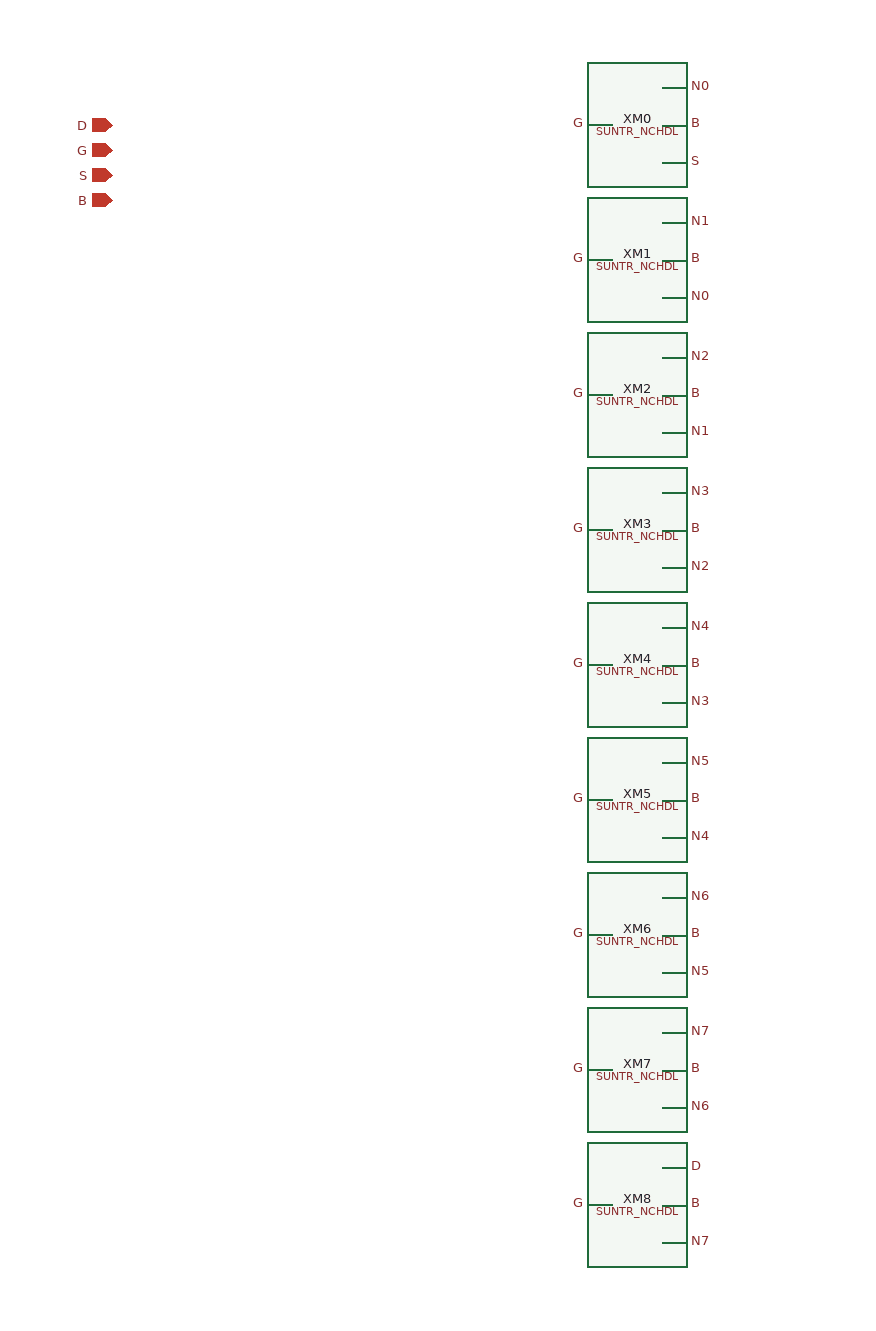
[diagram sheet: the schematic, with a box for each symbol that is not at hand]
v {xschem version=3.0.0 file_version=1.2 }
G {}
K {}
V {}
S {}
E {}
C {devices/iopin.sym} 0 0 0 0{name=p0 lab=D}
C {devices/iopin.sym} 0 20 0 0{name=p1 lab=G}
C {devices/iopin.sym} 0 40 0 0{name=p2 lab=S}
C {devices/iopin.sym} 0 60 0 0{name=p3 lab=B}
C {SUN_TR_SKY130NM/SUNTR_NCHDL.sym} 400 0 0 0 {name=XM0}
N 460.0 -30.0 440.0 -30.0{lab=N0}
C {devices/lab_pin.sym} 460.0 -30.0 2 0  {name=l0 sig_type=std_logic lab=N0 }
N 380.0 0.0 400.0 0.0{lab=G}
C {devices/lab_pin.sym} 380.0 0.0 0 0  {name=l1 sig_type=std_logic lab=G }
N 460.0 30.0 440.0 30.0{lab=S}
C {devices/lab_pin.sym} 460.0 30.0 2 0  {name=l2 sig_type=std_logic lab=S }
N 460.0 0.0 440.0 0.0{lab=B}
C {devices/lab_pin.sym} 460.0 0.0 2 0  {name=l3 sig_type=std_logic lab=B }
C {SUN_TR_SKY130NM/SUNTR_NCHDL.sym} 400 108.0 0 0 {name=XM1}
N 460.0 78.0 440.0 78.0{lab=N1}
C {devices/lab_pin.sym} 460.0 78.0 2 0  {name=l4 sig_type=std_logic lab=N1 }
N 380.0 108.0 400.0 108.0{lab=G}
C {devices/lab_pin.sym} 380.0 108.0 0 0  {name=l5 sig_type=std_logic lab=G }
N 460.0 138.0 440.0 138.0{lab=N0}
C {devices/lab_pin.sym} 460.0 138.0 2 0  {name=l6 sig_type=std_logic lab=N0 }
N 460.0 108.0 440.0 108.0{lab=B}
C {devices/lab_pin.sym} 460.0 108.0 2 0  {name=l7 sig_type=std_logic lab=B }
C {SUN_TR_SKY130NM/SUNTR_NCHDL.sym} 400 216.0 0 0 {name=XM2}
N 460.0 186.0 440.0 186.0{lab=N2}
C {devices/lab_pin.sym} 460.0 186.0 2 0  {name=l8 sig_type=std_logic lab=N2 }
N 380.0 216.0 400.0 216.0{lab=G}
C {devices/lab_pin.sym} 380.0 216.0 0 0  {name=l9 sig_type=std_logic lab=G }
N 460.0 246.0 440.0 246.0{lab=N1}
C {devices/lab_pin.sym} 460.0 246.0 2 0  {name=l10 sig_type=std_logic lab=N1 }
N 460.0 216.0 440.0 216.0{lab=B}
C {devices/lab_pin.sym} 460.0 216.0 2 0  {name=l11 sig_type=std_logic lab=B }
C {SUN_TR_SKY130NM/SUNTR_NCHDL.sym} 400 324.0 0 0 {name=XM3}
N 460.0 294.0 440.0 294.0{lab=N3}
C {devices/lab_pin.sym} 460.0 294.0 2 0  {name=l12 sig_type=std_logic lab=N3 }
N 380.0 324.0 400.0 324.0{lab=G}
C {devices/lab_pin.sym} 380.0 324.0 0 0  {name=l13 sig_type=std_logic lab=G }
N 460.0 354.0 440.0 354.0{lab=N2}
C {devices/lab_pin.sym} 460.0 354.0 2 0  {name=l14 sig_type=std_logic lab=N2 }
N 460.0 324.0 440.0 324.0{lab=B}
C {devices/lab_pin.sym} 460.0 324.0 2 0  {name=l15 sig_type=std_logic lab=B }
C {SUN_TR_SKY130NM/SUNTR_NCHDL.sym} 400 432.0 0 0 {name=XM4}
N 460.0 402.0 440.0 402.0{lab=N4}
C {devices/lab_pin.sym} 460.0 402.0 2 0  {name=l16 sig_type=std_logic lab=N4 }
N 380.0 432.0 400.0 432.0{lab=G}
C {devices/lab_pin.sym} 380.0 432.0 0 0  {name=l17 sig_type=std_logic lab=G }
N 460.0 462.0 440.0 462.0{lab=N3}
C {devices/lab_pin.sym} 460.0 462.0 2 0  {name=l18 sig_type=std_logic lab=N3 }
N 460.0 432.0 440.0 432.0{lab=B}
C {devices/lab_pin.sym} 460.0 432.0 2 0  {name=l19 sig_type=std_logic lab=B }
C {SUN_TR_SKY130NM/SUNTR_NCHDL.sym} 400 540.0 0 0 {name=XM5}
N 460.0 510.0 440.0 510.0{lab=N5}
C {devices/lab_pin.sym} 460.0 510.0 2 0  {name=l20 sig_type=std_logic lab=N5 }
N 380.0 540.0 400.0 540.0{lab=G}
C {devices/lab_pin.sym} 380.0 540.0 0 0  {name=l21 sig_type=std_logic lab=G }
N 460.0 570.0 440.0 570.0{lab=N4}
C {devices/lab_pin.sym} 460.0 570.0 2 0  {name=l22 sig_type=std_logic lab=N4 }
N 460.0 540.0 440.0 540.0{lab=B}
C {devices/lab_pin.sym} 460.0 540.0 2 0  {name=l23 sig_type=std_logic lab=B }
C {SUN_TR_SKY130NM/SUNTR_NCHDL.sym} 400 648.0 0 0 {name=XM6}
N 460.0 618.0 440.0 618.0{lab=N6}
C {devices/lab_pin.sym} 460.0 618.0 2 0  {name=l24 sig_type=std_logic lab=N6 }
N 380.0 648.0 400.0 648.0{lab=G}
C {devices/lab_pin.sym} 380.0 648.0 0 0  {name=l25 sig_type=std_logic lab=G }
N 460.0 678.0 440.0 678.0{lab=N5}
C {devices/lab_pin.sym} 460.0 678.0 2 0  {name=l26 sig_type=std_logic lab=N5 }
N 460.0 648.0 440.0 648.0{lab=B}
C {devices/lab_pin.sym} 460.0 648.0 2 0  {name=l27 sig_type=std_logic lab=B }
C {SUN_TR_SKY130NM/SUNTR_NCHDL.sym} 400 756.0 0 0 {name=XM7}
N 460.0 726.0 440.0 726.0{lab=N7}
C {devices/lab_pin.sym} 460.0 726.0 2 0  {name=l28 sig_type=std_logic lab=N7 }
N 380.0 756.0 400.0 756.0{lab=G}
C {devices/lab_pin.sym} 380.0 756.0 0 0  {name=l29 sig_type=std_logic lab=G }
N 460.0 786.0 440.0 786.0{lab=N6}
C {devices/lab_pin.sym} 460.0 786.0 2 0  {name=l30 sig_type=std_logic lab=N6 }
N 460.0 756.0 440.0 756.0{lab=B}
C {devices/lab_pin.sym} 460.0 756.0 2 0  {name=l31 sig_type=std_logic lab=B }
C {SUN_TR_SKY130NM/SUNTR_NCHDL.sym} 400 864.0 0 0 {name=XM8}
N 460.0 834.0 440.0 834.0{lab=D}
C {devices/lab_pin.sym} 460.0 834.0 2 0  {name=l32 sig_type=std_logic lab=D }
N 380.0 864.0 400.0 864.0{lab=G}
C {devices/lab_pin.sym} 380.0 864.0 0 0  {name=l33 sig_type=std_logic lab=G }
N 460.0 894.0 440.0 894.0{lab=N7}
C {devices/lab_pin.sym} 460.0 894.0 2 0  {name=l34 sig_type=std_logic lab=N7 }
N 460.0 864.0 440.0 864.0{lab=B}
C {devices/lab_pin.sym} 460.0 864.0 2 0  {name=l35 sig_type=std_logic lab=B }
